VERSION 5.8 ;
BUSBITCHARS "[]" ;
DIVIDERCHAR "/" ;
UNITS
    DATABASE MICRONS 1000 ;
END UNITS

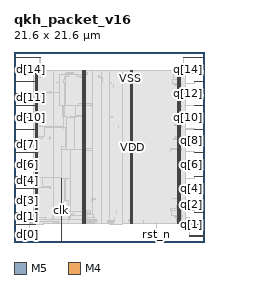
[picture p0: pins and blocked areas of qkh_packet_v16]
MACRO qkh_packet_v16
  FOREIGN qkh_packet_v16 0 0 ;
  CLASS BLOCK ;
  SIZE 21.6 BY 21.6 ;
  PIN clk
    DIRECTION INPUT ;
    USE SIGNAL ;
    PORT
      LAYER M5 ;
        RECT  5.376 0 5.4 0.084 ;
    END
    PORT
      LAYER M5 ;
        RECT  5.376 0.016 5.4 7.189 ;
    END
  END clk
  PIN d[0]
    DIRECTION INPUT ;
    USE SIGNAL ;
    PORT
      LAYER M4 ;
        RECT  0 0.672 0.084 0.696 ;
    END
    PORT
      LAYER M4 ;
        RECT  0.06 0.672 1.757 0.696 ;
    END
  END d[0]
  PIN d[10]
    DIRECTION INPUT ;
    USE SIGNAL ;
    PORT
      LAYER M4 ;
        RECT  0 14.16 0.084 14.184 ;
    END
    PORT
      LAYER M4 ;
        RECT  0.06 14.16 2.408 14.184 ;
    END
  END d[10]
  PIN d[11]
    DIRECTION INPUT ;
    USE SIGNAL ;
    PORT
      LAYER M4 ;
        RECT  0 15.504 0.084 15.528 ;
    END
    PORT
      LAYER M4 ;
        RECT  0.06 15.504 2.408 15.528 ;
    END
  END d[11]
  PIN d[12]
    DIRECTION INPUT ;
    USE SIGNAL ;
    PORT
      LAYER M4 ;
        RECT  0 16.848 0.084 16.872 ;
    END
    PORT
      LAYER M4 ;
        RECT  0.06 16.848 2.408 16.872 ;
    END
  END d[12]
  PIN d[13]
    DIRECTION INPUT ;
    USE SIGNAL ;
    PORT
      LAYER M4 ;
        RECT  0 18.192 0.084 18.216 ;
    END
    PORT
      LAYER M4 ;
        RECT  0.06 18.192 2.408 18.216 ;
    END
  END d[13]
  PIN d[14]
    DIRECTION INPUT ;
    USE SIGNAL ;
    PORT
      LAYER M4 ;
        RECT  0 19.584 0.084 19.608 ;
    END
    PORT
      LAYER M4 ;
        RECT  0.06 19.584 0.569 19.608 ;
    END
  END d[14]
  PIN d[15]
    DIRECTION INPUT ;
    USE SIGNAL ;
    PORT
      LAYER M4 ;
        RECT  0 20.928 0.084 20.952 ;
    END
    PORT
      LAYER M4 ;
        RECT  0.06 20.928 2.981 20.952 ;
    END
  END d[15]
  PIN d[1]
    DIRECTION INPUT ;
    USE SIGNAL ;
    PORT
      LAYER M4 ;
        RECT  0 2.016 0.084 2.04 ;
    END
    PORT
      LAYER M4 ;
        RECT  0.06 2.016 2.408 2.04 ;
    END
  END d[1]
  PIN d[2]
    DIRECTION INPUT ;
    USE SIGNAL ;
    PORT
      LAYER M4 ;
        RECT  0 3.36 0.084 3.384 ;
    END
    PORT
      LAYER M4 ;
        RECT  0.06 3.36 2.408 3.384 ;
    END
  END d[2]
  PIN d[3]
    DIRECTION INPUT ;
    USE SIGNAL ;
    PORT
      LAYER M4 ;
        RECT  0 4.704 0.084 4.728 ;
    END
    PORT
      LAYER M4 ;
        RECT  0.06 4.704 2.408 4.728 ;
    END
  END d[3]
  PIN d[4]
    DIRECTION INPUT ;
    USE SIGNAL ;
    PORT
      LAYER M4 ;
        RECT  0 6.048 0.084 6.072 ;
    END
    PORT
      LAYER M4 ;
        RECT  0.06 6.048 2.408 6.072 ;
    END
  END d[4]
  PIN d[5]
    DIRECTION INPUT ;
    USE SIGNAL ;
    PORT
      LAYER M4 ;
        RECT  0 7.392 0.084 7.416 ;
    END
    PORT
      LAYER M4 ;
        RECT  0.06 7.392 2.408 7.416 ;
    END
  END d[5]
  PIN d[6]
    DIRECTION INPUT ;
    USE SIGNAL ;
    PORT
      LAYER M4 ;
        RECT  0 8.784 0.084 8.808 ;
    END
    PORT
      LAYER M4 ;
        RECT  0.06 8.784 2.408 8.808 ;
    END
  END d[6]
  PIN d[7]
    DIRECTION INPUT ;
    USE SIGNAL ;
    PORT
      LAYER M4 ;
        RECT  0 10.128 0.084 10.152 ;
    END
    PORT
      LAYER M4 ;
        RECT  0.06 10.128 2.408 10.152 ;
    END
  END d[7]
  PIN d[8]
    DIRECTION INPUT ;
    USE SIGNAL ;
    PORT
      LAYER M4 ;
        RECT  0 11.472 0.084 11.496 ;
    END
    PORT
      LAYER M4 ;
        RECT  0.06 11.472 2.408 11.496 ;
    END
  END d[8]
  PIN d[9]
    DIRECTION INPUT ;
    USE SIGNAL ;
    PORT
      LAYER M4 ;
        RECT  0 12.816 0.084 12.84 ;
    END
    PORT
      LAYER M4 ;
        RECT  0.06 12.816 2.408 12.84 ;
    END
  END d[9]
  PIN q[0]
    DIRECTION OUTPUT ;
    USE SIGNAL ;
    PORT
      LAYER M4 ;
        RECT  21.516 0.672 21.6 0.696 ;
    END
    PORT
      LAYER M4 ;
        RECT  19.897 0.672 21.564 0.696 ;
    END
  END q[0]
  PIN q[10]
    DIRECTION OUTPUT ;
    USE SIGNAL ;
    PORT
      LAYER M4 ;
        RECT  21.516 14.16 21.6 14.184 ;
    END
    PORT
      LAYER M4 ;
        RECT  20.473 14.16 21.564 14.184 ;
    END
  END q[10]
  PIN q[11]
    DIRECTION OUTPUT ;
    USE SIGNAL ;
    PORT
      LAYER M4 ;
        RECT  21.516 15.504 21.6 15.528 ;
    END
    PORT
      LAYER M4 ;
        RECT  20.473 15.504 21.564 15.528 ;
    END
  END q[11]
  PIN q[12]
    DIRECTION OUTPUT ;
    USE SIGNAL ;
    PORT
      LAYER M4 ;
        RECT  21.516 16.848 21.6 16.872 ;
    END
    PORT
      LAYER M4 ;
        RECT  21.481 16.848 21.564 16.872 ;
    END
  END q[12]
  PIN q[13]
    DIRECTION OUTPUT ;
    USE SIGNAL ;
    PORT
      LAYER M4 ;
        RECT  21.516 18.192 21.6 18.216 ;
    END
    PORT
      LAYER M4 ;
        RECT  20.473 18.192 21.564 18.216 ;
    END
  END q[13]
  PIN q[14]
    DIRECTION OUTPUT ;
    USE SIGNAL ;
    PORT
      LAYER M4 ;
        RECT  21.516 19.584 21.6 19.608 ;
    END
    PORT
      LAYER M4 ;
        RECT  21.481 19.584 21.564 19.608 ;
    END
  END q[14]
  PIN q[15]
    DIRECTION OUTPUT ;
    USE SIGNAL ;
    PORT
      LAYER M4 ;
        RECT  21.516 20.928 21.6 20.952 ;
    END
    PORT
      LAYER M4 ;
        RECT  19.285 20.928 21.564 20.952 ;
    END
  END q[15]
  PIN q[1]
    DIRECTION OUTPUT ;
    USE SIGNAL ;
    PORT
      LAYER M4 ;
        RECT  21.516 2.016 21.6 2.04 ;
    END
    PORT
      LAYER M4 ;
        RECT  20.473 2.016 21.564 2.04 ;
    END
  END q[1]
  PIN q[2]
    DIRECTION OUTPUT ;
    USE SIGNAL ;
    PORT
      LAYER M4 ;
        RECT  21.516 3.36 21.6 3.384 ;
    END
    PORT
      LAYER M4 ;
        RECT  20.473 3.36 21.564 3.384 ;
    END
  END q[2]
  PIN q[3]
    DIRECTION OUTPUT ;
    USE SIGNAL ;
    PORT
      LAYER M4 ;
        RECT  21.516 4.704 21.6 4.728 ;
    END
    PORT
      LAYER M4 ;
        RECT  20.473 4.704 21.564 4.728 ;
    END
  END q[3]
  PIN q[4]
    DIRECTION OUTPUT ;
    USE SIGNAL ;
    PORT
      LAYER M4 ;
        RECT  21.516 6.048 21.6 6.072 ;
    END
    PORT
      LAYER M4 ;
        RECT  20.473 6.048 21.564 6.072 ;
    END
  END q[4]
  PIN q[5]
    DIRECTION OUTPUT ;
    USE SIGNAL ;
    PORT
      LAYER M4 ;
        RECT  21.516 7.392 21.6 7.416 ;
    END
    PORT
      LAYER M4 ;
        RECT  20.473 7.392 21.564 7.416 ;
    END
  END q[5]
  PIN q[6]
    DIRECTION OUTPUT ;
    USE SIGNAL ;
    PORT
      LAYER M4 ;
        RECT  21.516 8.784 21.6 8.808 ;
    END
    PORT
      LAYER M4 ;
        RECT  20.473 8.784 21.564 8.808 ;
    END
  END q[6]
  PIN q[7]
    DIRECTION OUTPUT ;
    USE SIGNAL ;
    PORT
      LAYER M4 ;
        RECT  21.516 10.128 21.6 10.152 ;
    END
    PORT
      LAYER M4 ;
        RECT  20.473 10.128 21.564 10.152 ;
    END
  END q[7]
  PIN q[8]
    DIRECTION OUTPUT ;
    USE SIGNAL ;
    PORT
      LAYER M4 ;
        RECT  21.516 11.472 21.6 11.496 ;
    END
    PORT
      LAYER M4 ;
        RECT  21.481 11.472 21.564 11.496 ;
    END
  END q[8]
  PIN q[9]
    DIRECTION OUTPUT ;
    USE SIGNAL ;
    PORT
      LAYER M4 ;
        RECT  21.516 12.816 21.6 12.84 ;
    END
    PORT
      LAYER M4 ;
        RECT  20.473 12.816 21.564 12.84 ;
    END
  END q[9]
  PIN rst_n
    DIRECTION INPUT ;
    USE SIGNAL ;
    PORT
      LAYER M5 ;
        RECT  16.176 0 16.2 0.084 ;
    END
    PORT
      LAYER M5 ;
        RECT  16.176 0.016 16.2 0.611 ;
    END
  END rst_n
  PIN VDD
    DIRECTION INOUT ;
    USE POWER ;
    PORT
      LAYER M5 ;
        RECT  18.792 2.151 18.912 19.449 ;
        RECT  13.392 2.151 13.512 19.449 ;
        RECT  7.992 2.151 8.112 19.449 ;
        RECT  2.592 2.151 2.712 19.449 ;
    END
  END VDD
  PIN VSS
    DIRECTION INOUT ;
    USE GROUND ;
    PORT
      LAYER M5 ;
        RECT  18.6 2.137 18.72 19.463 ;
        RECT  13.2 2.137 13.32 19.463 ;
        RECT  7.8 2.137 7.92 19.463 ;
        RECT  2.4 2.137 2.52 19.463 ;
    END
  END VSS
  # OT_OBS_CLOSED layer=M5 d_um=1.536 added=3
  OBS
    LAYER RVTN ;
     RECT  2.16 2.16 19.44 2.295 ;
     RECT  2.16 2.565 19.44 2.835 ;
     RECT  2.16 3.105 19.44 3.375 ;
     RECT  2.16 3.645 19.44 3.915 ;
     RECT  2.16 4.185 19.44 4.455 ;
     RECT  2.16 4.725 19.44 4.995 ;
     RECT  2.16 5.265 19.44 5.535 ;
     RECT  2.16 5.805 19.44 6.075 ;
     RECT  2.16 6.345 19.44 6.615 ;
     RECT  2.16 6.885 19.44 7.155 ;
     RECT  2.16 7.425 19.44 7.695 ;
     RECT  2.16 7.965 19.44 8.235 ;
     RECT  2.16 8.505 19.44 8.775 ;
     RECT  2.16 9.045 19.44 9.315 ;
     RECT  2.16 9.585 19.44 9.855 ;
     RECT  2.16 10.125 19.44 10.395 ;
     RECT  2.16 10.665 19.44 10.935 ;
     RECT  2.16 11.205 19.44 11.475 ;
     RECT  2.16 11.745 19.44 12.015 ;
     RECT  2.16 12.285 19.44 12.555 ;
     RECT  2.16 12.825 19.44 13.095 ;
     RECT  2.16 13.365 19.44 13.635 ;
     RECT  2.16 13.905 19.44 14.175 ;
     RECT  2.16 14.445 19.44 14.715 ;
     RECT  2.16 14.985 19.44 15.255 ;
     RECT  2.16 15.525 19.44 15.795 ;
     RECT  2.16 16.065 19.44 16.335 ;
     RECT  2.16 16.605 19.44 16.875 ;
     RECT  2.16 17.145 19.44 17.415 ;
     RECT  2.16 17.685 19.44 17.955 ;
     RECT  2.16 18.225 19.44 18.495 ;
     RECT  2.16 18.765 19.44 19.035 ;
     RECT  2.16 19.305 19.44 19.44 ;
    LAYER RVTP ;
     RECT  2.16 2.295 19.44 2.565 ;
     RECT  2.16 2.835 19.44 3.105 ;
     RECT  2.16 3.375 19.44 3.645 ;
     RECT  2.16 3.915 19.44 4.185 ;
     RECT  2.16 4.455 19.44 4.725 ;
     RECT  2.16 4.995 19.44 5.265 ;
     RECT  2.16 5.535 19.44 5.805 ;
     RECT  2.16 6.075 19.44 6.345 ;
     RECT  2.16 6.615 19.44 6.885 ;
     RECT  2.16 7.155 19.44 7.425 ;
     RECT  2.16 7.695 19.44 7.965 ;
     RECT  2.16 8.235 19.44 8.505 ;
     RECT  2.16 8.775 19.44 9.045 ;
     RECT  2.16 9.315 19.44 9.585 ;
     RECT  2.16 9.855 19.44 10.125 ;
     RECT  2.16 10.395 19.44 10.665 ;
     RECT  2.16 10.935 19.44 11.205 ;
     RECT  2.16 11.475 19.44 11.745 ;
     RECT  2.16 12.015 19.44 12.285 ;
     RECT  2.16 12.555 19.44 12.825 ;
     RECT  2.16 13.095 19.44 13.365 ;
     RECT  2.16 13.635 19.44 13.905 ;
     RECT  2.16 14.175 19.44 14.445 ;
     RECT  2.16 14.715 19.44 14.985 ;
     RECT  2.16 15.255 19.44 15.525 ;
     RECT  2.16 15.795 19.44 16.065 ;
     RECT  2.16 16.335 19.44 16.605 ;
     RECT  2.16 16.875 19.44 17.145 ;
     RECT  2.16 17.415 19.44 17.685 ;
     RECT  2.16 17.955 19.44 18.225 ;
     RECT  2.16 18.495 19.44 18.765 ;
     RECT  2.16 19.035 19.44 19.305 ;
    LAYER M1 ;
     RECT  2.16 2.151 19.44 19.449 ;
    LAYER M2 ;
     RECT  1.723 2.232 2.16 2.25 ;
     RECT  0.535 19.35 2.16 19.368 ;
     RECT  2.16 2.151 4.495 19.449 ;
     RECT  4.495 2.106 8.959 19.449 ;
     RECT  8.959 2.07 9.959 19.449 ;
     RECT  9.959 2.106 10.831 19.449 ;
     RECT  10.831 2.034 12.335 19.449 ;
     RECT  12.335 2.151 19.44 19.449 ;
     RECT  19.44 2.196 19.931 2.754 ;
     RECT  19.931 2.196 20.507 2.214 ;
     RECT  19.44 3.546 20.507 3.564 ;
     RECT  19.44 4.626 20.507 4.644 ;
     RECT  19.44 5.886 20.507 5.904 ;
     RECT  19.44 7.236 20.507 7.254 ;
     RECT  19.44 8.946 20.507 8.964 ;
     RECT  19.44 10.296 20.507 10.314 ;
     RECT  19.44 12.834 20.507 12.852 ;
     RECT  19.44 13.986 20.507 14.004 ;
     RECT  19.44 15.498 20.507 15.516 ;
     RECT  19.44 18.036 20.507 18.054 ;
     RECT  19.44 11.376 21.515 11.394 ;
     RECT  19.44 16.506 21.515 16.524 ;
     RECT  19.44 19.116 21.515 19.134 ;
    LAYER M3 ;
     RECT  19.908 0.667 19.926 2.011 ;
     RECT  10.836 2.029 10.854 2.101 ;
     RECT  1.728 0.667 1.746 2.143 ;
     RECT  7.815 2.143 7.905 2.191 ;
     RECT  8.964 2.065 8.982 2.191 ;
     RECT  18.615 2.143 18.705 2.191 ;
     RECT  9.936 2.065 9.954 2.219 ;
     RECT  19.908 2.011 20.502 2.219 ;
     RECT  1.728 2.143 2.505 2.255 ;
     RECT  16.164 0.571 16.182 2.255 ;
     RECT  2.415 2.255 2.505 2.263 ;
     RECT  3.276 2.011 3.294 2.263 ;
     RECT  4.5 2.101 4.518 2.263 ;
     RECT  10.836 2.101 11.286 2.263 ;
     RECT  4.5 2.263 5.058 2.299 ;
     RECT  7.815 2.191 9.126 2.299 ;
     RECT  4.248 2.299 5.058 2.335 ;
     RECT  2.415 2.263 3.294 2.371 ;
     RECT  4.068 2.335 5.058 2.371 ;
     RECT  10.656 2.263 11.286 2.371 ;
     RECT  13.215 2.143 13.305 2.371 ;
     RECT  18.615 2.191 19.098 2.371 ;
     RECT  10.656 2.371 11.394 2.399 ;
     RECT  14.76 2.263 14.778 2.399 ;
     RECT  13.068 2.371 13.305 2.413 ;
     RECT  7.815 2.299 9.45 2.461 ;
     RECT  7.668 2.461 9.45 2.489 ;
     RECT  12.312 2.029 12.33 2.489 ;
     RECT  2.415 2.371 5.058 2.525 ;
     RECT  7.668 2.489 9.342 2.525 ;
     RECT  2.415 2.525 4.806 2.561 ;
     RECT  13.068 2.413 13.497 2.561 ;
     RECT  6.228 2.299 6.246 2.569 ;
     RECT  7.668 2.525 9.126 2.569 ;
     RECT  2.415 2.561 4.338 2.573 ;
     RECT  4.32 2.573 4.338 2.759 ;
     RECT  11.376 2.399 11.394 2.759 ;
     RECT  19.908 2.219 19.926 2.759 ;
     RECT  18.468 2.371 19.098 2.767 ;
     RECT  2.415 2.573 3.582 2.795 ;
     RECT  6.228 2.569 9.126 2.795 ;
     RECT  18.288 2.767 19.098 2.803 ;
     RECT  3.564 2.795 3.582 2.831 ;
     RECT  18.216 2.803 19.098 2.875 ;
     RECT  18.216 2.875 19.134 3.001 ;
     RECT  17.856 3.001 19.134 3.029 ;
     RECT  6.228 2.795 8.982 3.101 ;
     RECT  6.228 3.101 8.73 3.271 ;
     RECT  2.415 2.795 2.826 3.389 ;
     RECT  6.192 3.271 8.73 3.407 ;
     RECT  6.192 3.407 6.426 3.443 ;
     RECT  17.856 3.029 18.99 3.541 ;
     RECT  6.192 3.443 6.246 3.569 ;
     RECT  7.308 3.407 8.73 3.569 ;
     RECT  11.628 3.343 11.646 3.569 ;
     RECT  20.484 3.355 20.502 3.569 ;
     RECT  4.536 3.379 4.554 3.605 ;
     RECT  7.416 3.569 8.226 3.605 ;
     RECT  7.416 3.605 8.154 3.641 ;
     RECT  7.416 3.641 8.097 3.749 ;
     RECT  17.784 3.541 18.99 3.839 ;
     RECT  18.504 3.839 18.99 4.109 ;
     RECT  2.415 3.389 2.697 4.657 ;
     RECT  6.228 3.569 6.246 4.693 ;
     RECT  5.796 4.693 6.246 4.721 ;
     RECT  2.412 4.657 2.697 4.733 ;
     RECT  20.484 4.621 20.502 4.733 ;
     RECT  8.82 4.657 8.838 4.801 ;
     RECT  18.615 4.109 18.897 4.891 ;
     RECT  8.82 4.801 9.306 4.919 ;
     RECT  8.82 4.919 8.838 4.955 ;
     RECT  18 4.891 18.897 4.991 ;
     RECT  18.615 4.991 18.897 5.845 ;
     RECT  18.615 5.845 19.098 5.999 ;
     RECT  2.415 4.733 2.697 6.007 ;
     RECT  2.304 6.007 2.697 6.077 ;
     RECT  20.484 5.881 20.502 6.077 ;
     RECT  4.176 6.079 4.194 6.115 ;
     RECT  2.415 6.077 2.697 6.151 ;
     RECT  4.068 6.115 4.194 6.151 ;
     RECT  2.415 6.151 4.194 6.269 ;
     RECT  2.415 6.269 3.114 6.305 ;
     RECT  18.615 5.999 18.897 7.051 ;
     RECT  18.615 7.051 19.098 7.151 ;
     RECT  5.796 4.721 5.814 7.189 ;
     RECT  5.796 7.189 5.922 7.231 ;
     RECT  6.84 7.123 6.858 7.231 ;
     RECT  5.796 7.231 6.858 7.357 ;
     RECT  5.652 7.357 6.858 7.373 ;
     RECT  4.824 7.339 4.842 7.385 ;
     RECT  5.652 7.373 5.814 7.421 ;
     RECT  20.484 7.231 20.502 7.421 ;
     RECT  5.652 7.421 5.67 7.655 ;
     RECT  2.415 6.305 2.697 8.779 ;
     RECT  20.484 8.779 20.502 8.969 ;
     RECT  6.84 7.373 6.858 8.977 ;
     RECT  7.815 3.749 8.097 8.977 ;
     RECT  2.304 8.779 2.697 9.005 ;
     RECT  6.408 8.977 8.097 9.053 ;
     RECT  18.615 7.151 18.897 9.085 ;
     RECT  18.615 9.085 19.062 9.211 ;
     RECT  10.872 8.941 10.89 9.239 ;
     RECT  18.54 9.211 19.062 9.239 ;
     RECT  6.84 9.053 8.097 9.275 ;
     RECT  18.54 9.239 18.897 9.311 ;
     RECT  2.415 9.005 2.697 10.123 ;
     RECT  20.484 10.123 20.502 10.319 ;
     RECT  2.415 10.123 2.79 10.355 ;
     RECT  7.815 9.275 8.097 10.399 ;
     RECT  7.815 10.399 8.586 10.435 ;
     RECT  18.615 9.311 18.897 10.435 ;
     RECT  17.784 10.291 17.802 10.561 ;
     RECT  18.615 10.435 19.098 10.561 ;
     RECT  7.815 10.435 8.874 10.589 ;
     RECT  17.784 10.561 19.098 10.589 ;
     RECT  18.144 10.589 18.897 10.661 ;
     RECT  5.904 10.831 5.922 10.843 ;
     RECT  5.652 10.843 5.922 10.877 ;
     RECT  5.652 10.877 5.67 10.895 ;
     RECT  2.415 10.355 2.697 11.467 ;
     RECT  21.492 11.371 21.51 11.501 ;
     RECT  18.615 10.661 18.897 11.515 ;
     RECT  18.615 11.515 19.098 11.641 ;
     RECT  2.304 11.467 2.697 11.705 ;
     RECT  4.032 11.677 4.05 11.713 ;
     RECT  18.108 11.641 19.098 11.741 ;
     RECT  2.415 11.705 2.697 11.749 ;
     RECT  4.032 11.713 4.194 11.849 ;
     RECT  18.324 11.741 19.098 11.939 ;
     RECT  4.032 11.849 4.05 11.975 ;
     RECT  2.415 11.749 3.222 11.981 ;
     RECT  20.484 12.811 20.502 12.857 ;
     RECT  18.615 11.939 18.897 12.865 ;
     RECT  4.824 13.051 4.842 13.091 ;
     RECT  5.652 12.865 5.67 13.099 ;
     RECT  5.652 13.099 5.814 13.163 ;
     RECT  18.615 12.865 19.098 13.261 ;
     RECT  5.796 13.163 5.814 13.289 ;
     RECT  11.916 12.991 11.934 13.289 ;
     RECT  18.216 13.261 19.098 13.361 ;
     RECT  18.615 13.361 19.098 14.099 ;
     RECT  2.415 11.981 2.697 14.107 ;
     RECT  6.84 9.275 6.858 14.155 ;
     RECT  6.408 14.155 6.858 14.179 ;
     RECT  2.415 14.107 2.826 14.189 ;
     RECT  20.484 13.981 20.502 14.189 ;
     RECT  6.408 14.179 6.966 14.215 ;
     RECT  7.815 10.589 8.097 14.215 ;
     RECT  6.408 14.215 8.097 14.243 ;
     RECT  11.124 14.107 11.142 14.279 ;
     RECT  6.948 14.243 8.097 14.369 ;
     RECT  5.544 14.251 5.562 14.587 ;
     RECT  5.544 14.587 5.67 14.747 ;
     RECT  18.615 14.099 18.897 15.421 ;
     RECT  2.415 14.189 2.697 15.457 ;
     RECT  5.544 14.747 5.562 15.493 ;
     RECT  6.948 14.369 6.966 15.493 ;
     RECT  7.815 14.369 8.097 15.493 ;
     RECT  8.82 15.457 8.838 15.493 ;
     RECT  6.948 15.493 8.838 15.521 ;
     RECT  18.615 15.421 19.098 15.521 ;
     RECT  2.304 15.457 2.697 15.533 ;
     RECT  5.544 15.493 5.814 15.533 ;
     RECT  20.484 15.493 20.502 15.533 ;
     RECT  7.38 15.521 8.838 15.719 ;
     RECT  8.82 15.719 8.838 15.755 ;
     RECT  18.615 15.521 18.897 16.501 ;
     RECT  18.615 16.501 19.098 16.601 ;
     RECT  18.615 16.601 18.897 16.681 ;
     RECT  18.252 16.681 18.897 16.799 ;
     RECT  2.415 15.533 2.697 16.807 ;
     RECT  2.304 16.807 2.697 16.877 ;
     RECT  21.492 16.501 21.51 16.877 ;
     RECT  4.176 16.879 4.194 16.915 ;
     RECT  2.415 16.877 2.697 16.939 ;
     RECT  2.415 16.939 3.258 16.979 ;
     RECT  4.068 16.915 4.194 17.069 ;
     RECT  18.615 16.799 18.897 17.761 ;
     RECT  18.288 17.761 18.897 17.851 ;
     RECT  11.304 17.581 11.322 17.879 ;
     RECT  18.288 17.851 19.098 17.951 ;
     RECT  18.288 17.951 18.897 17.995 ;
     RECT  5.796 15.533 5.814 18.157 ;
     RECT  4.824 18.139 4.842 18.185 ;
     RECT  11.088 18.031 11.106 18.185 ;
     RECT  20.484 18.031 20.502 18.221 ;
     RECT  18 17.995 18.897 18.419 ;
     RECT  5.652 18.157 5.814 18.455 ;
     RECT  7.815 15.719 8.097 18.661 ;
     RECT  10.044 18.121 10.062 18.661 ;
     RECT  9.648 18.661 10.062 18.689 ;
     RECT  2.415 16.979 2.697 18.697 ;
     RECT  5.796 18.455 5.814 18.841 ;
     RECT  7.596 18.661 8.097 18.841 ;
     RECT  12.168 18.391 12.186 18.841 ;
     RECT  5.796 18.841 6.246 18.869 ;
     RECT  9.648 18.689 9.666 18.959 ;
     RECT  11.952 18.841 12.186 18.959 ;
     RECT  18.144 18.419 18.897 18.995 ;
     RECT  5.868 18.869 6.246 19.075 ;
     RECT  7.128 18.841 8.097 19.075 ;
     RECT  5.868 19.075 8.334 19.085 ;
     RECT  5.868 19.085 6.786 19.103 ;
     RECT  13.215 2.561 13.497 19.187 ;
     RECT  18.615 18.995 18.897 19.201 ;
     RECT  6.012 19.103 6.786 19.229 ;
     RECT  7.74 19.085 8.334 19.229 ;
     RECT  6.228 19.229 6.246 19.301 ;
     RECT  7.74 19.229 7.905 19.301 ;
     RECT  18.615 19.201 19.098 19.345 ;
     RECT  2.415 18.697 2.97 19.457 ;
     RECT  7.815 19.301 7.905 19.457 ;
     RECT  13.215 19.187 13.305 19.457 ;
     RECT  18.615 19.345 19.314 19.457 ;
     RECT  0.54 19.345 0.558 19.613 ;
     RECT  21.492 19.111 21.51 19.613 ;
     RECT  2.952 19.457 2.97 20.957 ;
     RECT  19.296 19.457 19.314 20.957 ;
    LAYER M4 ;
     RECT  2.408 2.016 2.512 19.452 ;
     RECT  2.512 2.016 2.704 19.182 ;
     RECT  2.704 10.128 2.801 10.152 ;
     RECT  2.704 3.36 2.837 3.384 ;
     RECT  2.704 14.16 2.837 14.184 ;
     RECT  2.704 6.192 3.299 6.216 ;
     RECT  2.704 2.016 3.305 2.328 ;
     RECT  2.704 11.952 3.443 11.976 ;
     RECT  3.305 2.304 4.237 2.328 ;
     RECT  4.237 2.304 4.277 2.568 ;
     RECT  4.813 18.144 5.125 18.168 ;
     RECT  2.704 16.944 5.171 16.968 ;
     RECT  5.125 18.144 5.171 19.08 ;
     RECT  5.533 14.256 5.605 14.28 ;
     RECT  5.125 15.504 5.605 15.528 ;
     RECT  2.704 13.056 5.651 13.08 ;
     RECT  5.605 14.16 5.692 15.528 ;
     RECT  2.704 7.344 5.852 7.368 ;
     RECT  5.852 7.2 5.939 7.368 ;
     RECT  5.365 10.848 5.939 10.872 ;
     RECT  5.692 14.16 5.939 14.28 ;
     RECT  5.939 7.248 6.257 7.368 ;
     RECT  4.277 2.544 6.36 2.568 ;
     RECT  6.36 2.544 6.419 3.432 ;
     RECT  5.939 14.16 6.437 14.184 ;
     RECT  6.257 7.248 6.467 7.272 ;
     RECT  6.38 9.024 6.467 9.048 ;
     RECT  6.419 3.072 7.808 3.432 ;
     RECT  6.421 10.464 7.808 10.488 ;
     RECT  5.692 15.504 7.808 15.528 ;
     RECT  5.171 19.056 7.808 19.08 ;
     RECT  7.808 2.148 7.912 19.452 ;
     RECT  7.912 2.352 8.104 19.182 ;
     RECT  8.104 2.352 8.243 2.376 ;
     RECT  8.104 3.408 8.243 3.432 ;
     RECT  13.208 2.148 13.312 19.452 ;
     RECT  13.312 2.418 13.504 19.182 ;
     RECT  16.153 0.576 16.237 0.6 ;
     RECT  18.608 2.148 18.712 19.452 ;
     RECT  18.712 2.418 18.904 19.182 ;
    LAYER M5 ;
     RECT  2.4 2.137 2.52 2.151 ;
     RECT  7.8 2.137 7.92 2.151 ;
     RECT  13.2 2.137 13.32 2.151 ;
     RECT  18.6 2.137 18.72 2.151 ;
     RECT  7.8 2.151 8.112 2.341 ;
     RECT  6.384 2.533 6.408 3.061 ;
     RECT  6.384 3.061 6.792 3.107 ;
     RECT  6.432 3.107 6.792 3.443 ;
     RECT  7.8 2.341 8.232 3.443 ;
     RECT  2.4 2.151 2.712 6.181 ;
     RECT  6.432 3.443 6.456 7.189 ;
     RECT  2.4 6.181 3.288 7.379 ;
     RECT  5.376 7.189 6.456 10.499 ;
     RECT  5.376 10.499 5.928 10.883 ;
     RECT  2.4 7.379 2.712 11.941 ;
     RECT  5.904 10.883 5.928 13.045 ;
     RECT  2.4 11.941 3.432 13.091 ;
     RECT  5.616 13.045 5.928 14.291 ;
     RECT  5.616 14.291 5.64 14.627 ;
     RECT  5.136 15.493 5.16 19.091 ;
     RECT  2.4 13.091 2.712 19.449 ;
     RECT  7.8 3.443 8.112 19.449 ;
     RECT  13.2 2.151 13.512 19.449 ;
     RECT  18.6 2.151 18.912 19.449 ;
     RECT  2.4 19.449 2.52 19.463 ;
     RECT  7.8 19.449 7.92 19.463 ;
     RECT  13.2 19.449 13.32 19.463 ;
     RECT  18.6 19.449 18.72 19.463 ;
     RECT  6.408 2.533 7.8 3.061 ;
     RECT  6.792 3.061 7.8 3.443 ;
     RECT  6.456 3.443 7.8 10.499 ;
  END
END qkh_packet_v16
END LIBRARY
